VERSION 5.7 ;
BUSBITCHARS "[]" ;
DIVIDERCHAR "/" ;
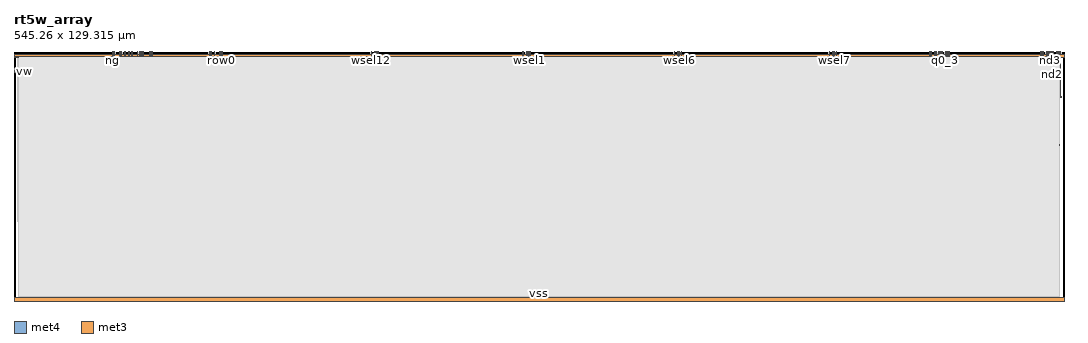
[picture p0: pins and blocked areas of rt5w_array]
MACRO rt5w_array
  CLASS BLOCK ;
  FOREIGN rt5w_array ;
  ORIGIN 0.000 117.195 ;
  SIZE 545.260 BY 129.315 ;
  SYMMETRY X Y ;
  PIN nd0
    DIRECTION INOUT ;
    USE SIGNAL ;
    PORT
      LAYER met4 ;
        RECT 485.380 11.970 485.680 12.120 ;
        RECT 485.365 11.470 485.695 11.970 ;
        RECT 485.380 9.620 485.680 11.470 ;
    END
  END nd0
  PIN nd1
    DIRECTION INOUT ;
    USE SIGNAL ;
    PORT
      LAYER met4 ;
        RECT 479.860 11.970 480.160 12.120 ;
        RECT 479.845 11.470 480.175 11.970 ;
        RECT 479.860 9.620 480.160 11.470 ;
    END
  END nd1
  PIN nd2
    DIRECTION INOUT ;
    USE SIGNAL ;
    PORT
      LAYER met4 ;
        RECT 543.340 11.970 543.640 12.120 ;
        RECT 543.325 11.470 543.655 11.970 ;
        RECT 543.340 -10.905 543.640 11.470 ;
        RECT 543.240 -11.405 543.740 -10.905 ;
    END
  END nd2
  PIN nd3
    DIRECTION INOUT ;
    USE SIGNAL ;
    PORT
      LAYER met4 ;
        RECT 537.820 11.970 538.120 12.120 ;
        RECT 537.805 11.470 538.135 11.970 ;
        RECT 537.820 9.620 538.120 11.470 ;
    END
  END nd3
  PIN ng
    DIRECTION INOUT ;
    USE SIGNAL ;
    PORT
      LAYER met4 ;
        RECT 51.140 11.970 51.440 12.120 ;
        RECT 51.125 11.470 51.455 11.970 ;
        RECT 51.140 9.620 51.440 11.470 ;
    END
  END ng
  PIN pg
    DIRECTION INOUT ;
    USE SIGNAL ;
    PORT
      LAYER met4 ;
        RECT 54.820 11.970 55.120 12.120 ;
        RECT 54.805 11.470 55.135 11.970 ;
        RECT 54.820 9.620 55.120 11.470 ;
    END
  END pg
  PIN pump_dn1
    DIRECTION INOUT ;
    USE SIGNAL ;
    PORT
      LAYER met4 ;
        RECT 66.780 11.970 67.080 12.120 ;
        RECT 66.765 11.470 67.095 11.970 ;
        RECT 66.780 9.620 67.080 11.470 ;
    END
  END pump_dn1
  PIN pump_dn2
    DIRECTION INOUT ;
    USE SIGNAL ;
    PORT
      LAYER met4 ;
        RECT 65.860 11.970 66.160 12.120 ;
        RECT 65.845 11.470 66.175 11.970 ;
        RECT 65.860 9.620 66.160 11.470 ;
    END
  END pump_dn2
  PIN pump_dn3
    DIRECTION INOUT ;
    USE SIGNAL ;
    PORT
      LAYER met4 ;
        RECT 71.380 11.970 71.680 12.120 ;
        RECT 71.365 11.470 71.695 11.970 ;
        RECT 71.380 9.620 71.680 11.470 ;
    END
  END pump_dn3
  PIN pump_up1
    DIRECTION INOUT ;
    USE SIGNAL ;
    PORT
      LAYER met4 ;
        RECT 64.940 11.970 65.240 12.120 ;
        RECT 64.925 11.470 65.255 11.970 ;
        RECT 64.940 9.620 65.240 11.470 ;
    END
  END pump_up1
  PIN pump_up2
    DIRECTION INOUT ;
    USE SIGNAL ;
    PORT
      LAYER met4 ;
        RECT 64.020 11.970 64.320 12.120 ;
        RECT 64.005 11.470 64.335 11.970 ;
        RECT 64.020 9.620 64.320 11.470 ;
    END
  END pump_up2
  PIN pump_up3
    DIRECTION INOUT ;
    USE SIGNAL ;
    PORT
      LAYER met4 ;
        RECT 70.460 11.970 70.760 12.120 ;
        RECT 70.445 11.470 70.775 11.970 ;
        RECT 70.460 9.620 70.760 11.470 ;
    END
  END pump_up3
  PIN q0_0
    DIRECTION INOUT ;
    USE SIGNAL ;
    PORT
      LAYER met4 ;
        RECT 484.460 11.970 484.760 12.120 ;
        RECT 484.445 11.470 484.775 11.970 ;
        RECT 484.460 9.620 484.760 11.470 ;
    END
  END q0_0
  PIN q0_1
    DIRECTION INOUT ;
    USE SIGNAL ;
    PORT
      LAYER met4 ;
        RECT 480.780 11.970 481.080 12.120 ;
        RECT 480.765 11.470 481.095 11.970 ;
        RECT 480.780 9.620 481.080 11.470 ;
    END
  END q0_1
  PIN q0_2
    DIRECTION INOUT ;
    USE SIGNAL ;
    PORT
      LAYER met4 ;
        RECT 481.700 11.970 482.000 12.120 ;
        RECT 481.685 11.470 482.015 11.970 ;
        RECT 481.700 9.620 482.000 11.470 ;
    END
  END q0_2
  PIN q0_3
    DIRECTION INOUT ;
    USE SIGNAL ;
    PORT
      LAYER met4 ;
        RECT 483.540 11.970 483.840 12.120 ;
        RECT 483.525 11.470 483.855 11.970 ;
        RECT 483.540 9.620 483.840 11.470 ;
    END
  END q0_3
  PIN q1_0
    DIRECTION INOUT ;
    USE SIGNAL ;
    PORT
      LAYER met4 ;
        RECT 478.940 11.970 479.240 12.120 ;
        RECT 478.925 11.470 479.255 11.970 ;
        RECT 478.940 9.620 479.240 11.470 ;
    END
  END q1_0
  PIN q1_1
    DIRECTION INOUT ;
    USE SIGNAL ;
    PORT
      LAYER met4 ;
        RECT 475.260 11.970 475.560 12.120 ;
        RECT 475.245 11.470 475.575 11.970 ;
        RECT 475.260 9.620 475.560 11.470 ;
    END
  END q1_1
  PIN q1_2
    DIRECTION INOUT ;
    USE SIGNAL ;
    PORT
      LAYER met4 ;
        RECT 476.180 11.970 476.480 12.120 ;
        RECT 476.165 11.470 476.495 11.970 ;
        RECT 476.180 9.620 476.480 11.470 ;
    END
  END q1_2
  PIN q1_3
    DIRECTION INOUT ;
    USE SIGNAL ;
    PORT
      LAYER met4 ;
        RECT 478.020 11.970 478.320 12.120 ;
        RECT 478.005 11.470 478.335 11.970 ;
        RECT 478.020 9.620 478.320 11.470 ;
    END
  END q1_3
  PIN q2_0
    DIRECTION INOUT ;
    USE SIGNAL ;
    PORT
      LAYER met4 ;
        RECT 542.760 -36.555 542.820 -36.055 ;
        RECT 542.420 11.970 542.720 12.120 ;
        RECT 542.405 11.470 542.735 11.970 ;
        RECT 542.420 9.620 542.720 11.470 ;
    END
  END q2_0
  PIN q2_1
    DIRECTION INOUT ;
    USE SIGNAL ;
    PORT
      LAYER met4 ;
        RECT 538.740 11.970 539.040 12.120 ;
        RECT 538.725 11.470 539.055 11.970 ;
        RECT 538.740 9.620 539.040 11.470 ;
    END
  END q2_1
  PIN q2_2
    DIRECTION INOUT ;
    USE SIGNAL ;
    PORT
      LAYER met4 ;
        RECT 539.660 11.970 539.960 12.120 ;
        RECT 539.645 11.470 539.975 11.970 ;
        RECT 539.660 9.620 539.960 11.470 ;
    END
  END q2_2
  PIN q2_3
    DIRECTION INOUT ;
    USE SIGNAL ;
    PORT
      LAYER met4 ;
        RECT 541.500 11.970 541.800 12.120 ;
        RECT 541.485 11.470 541.815 11.970 ;
        RECT 541.500 9.620 541.800 11.470 ;
    END
  END q2_3
  PIN q3_0
    DIRECTION INOUT ;
    USE SIGNAL ;
    PORT
      LAYER met4 ;
        RECT 536.900 11.970 537.200 12.120 ;
        RECT 536.885 11.470 537.215 11.970 ;
        RECT 536.900 9.620 537.200 11.470 ;
    END
  END q3_0
  PIN q3_1
    DIRECTION INOUT ;
    USE SIGNAL ;
    PORT
      LAYER met4 ;
        RECT 533.220 11.970 533.520 12.120 ;
        RECT 533.205 11.470 533.535 11.970 ;
        RECT 533.220 9.620 533.520 11.470 ;
    END
  END q3_1
  PIN q3_2
    DIRECTION INOUT ;
    USE SIGNAL ;
    PORT
      LAYER met4 ;
        RECT 534.140 11.970 534.440 12.120 ;
        RECT 534.125 11.470 534.455 11.970 ;
        RECT 534.140 9.620 534.440 11.470 ;
    END
  END q3_2
  PIN q3_3
    DIRECTION INOUT ;
    USE SIGNAL ;
    PORT
      LAYER met4 ;
        RECT 535.980 11.970 536.280 12.120 ;
        RECT 535.965 11.470 536.295 11.970 ;
        RECT 535.980 9.620 536.280 11.470 ;
    END
  END q3_3
  PIN row0
    DIRECTION INOUT ;
    USE SIGNAL ;
    PORT
      LAYER met4 ;
        RECT 107.720 11.970 108.020 12.120 ;
        RECT 107.705 11.470 108.035 11.970 ;
        RECT 107.720 9.620 108.020 11.470 ;
    END
  END row0
  PIN row1
    DIRECTION INOUT ;
    USE SIGNAL ;
    PORT
      LAYER met4 ;
        RECT 106.800 11.970 107.100 12.120 ;
        RECT 106.785 11.470 107.115 11.970 ;
        RECT 106.800 9.620 107.100 11.470 ;
    END
  END row1
  PIN row2
    DIRECTION INOUT ;
    USE SIGNAL ;
    PORT
      LAYER met4 ;
        RECT 104.040 11.970 104.340 12.120 ;
        RECT 104.025 11.470 104.355 11.970 ;
        RECT 104.040 9.620 104.340 11.470 ;
    END
  END row2
  PIN row3
    DIRECTION INOUT ;
    USE SIGNAL ;
    PORT
      LAYER met4 ;
        RECT 101.280 11.970 101.580 12.120 ;
        RECT 101.265 11.470 101.595 11.970 ;
        RECT 101.280 9.620 101.580 11.470 ;
    END
  END row3
  PIN vbn
    DIRECTION INOUT ;
    USE SIGNAL ;
    PORT
      LAYER met4 ;
        RECT 102.200 11.970 102.500 12.120 ;
        RECT 102.185 11.470 102.515 11.970 ;
        RECT 102.200 9.620 102.500 11.470 ;
    END
  END vbn
  PIN vdd
    DIRECTION INOUT ;
    USE SIGNAL ;
    PORT
      LAYER met3 ;
        RECT 0.000 9.120 2.500 9.620 ;
        RECT 0.000 9.620 542.760 10.920 ;
        RECT 542.760 9.120 545.260 10.920 ;
    END
  END vdd
  PIN vmid
    DIRECTION INOUT ;
    USE SIGNAL ;
    PORT
      LAYER met4 ;
        RECT 52.060 11.970 52.360 12.120 ;
        RECT 52.045 11.470 52.375 11.970 ;
        RECT 52.060 9.620 52.360 11.470 ;
    END
  END vmid
  PIN vss
    DIRECTION INOUT ;
    USE SIGNAL ;
    PORT
      LAYER met3 ;
        RECT 0.000 -117.195 545.260 -115.395 ;
    END
  END vss
  PIN vw
    DIRECTION INOUT ;
    USE SIGNAL ;
    PORT
      LAYER met3 ;
        RECT 0.000 1.690 2.500 1.990 ;
    END
  END vw
  PIN wsel0
    DIRECTION INOUT ;
    USE SIGNAL ;
    PORT
      LAYER met4 ;
        RECT 189.140 11.970 189.440 12.120 ;
        RECT 189.125 11.470 189.455 11.970 ;
        RECT 189.140 9.620 189.440 11.470 ;
    END
  END wsel0
  PIN wsel1
    DIRECTION INOUT ;
    USE SIGNAL ;
    PORT
      LAYER met4 ;
        RECT 267.800 11.970 268.100 12.120 ;
        RECT 267.785 11.470 268.115 11.970 ;
        RECT 267.800 9.620 268.100 11.470 ;
    END
  END wsel1
  PIN wsel10
    DIRECTION INOUT ;
    USE SIGNAL ;
    PORT
      LAYER met4 ;
        RECT 344.620 11.970 344.920 12.120 ;
        RECT 344.605 11.470 344.935 11.970 ;
        RECT 344.620 9.620 344.920 11.470 ;
    END
  END wsel10
  PIN wsel11
    DIRECTION INOUT ;
    USE SIGNAL ;
    PORT
      LAYER met4 ;
        RECT 425.120 11.970 425.420 12.120 ;
        RECT 425.105 11.470 425.435 11.970 ;
        RECT 425.120 9.620 425.420 11.470 ;
    END
  END wsel11
  PIN wsel12
    DIRECTION INOUT ;
    USE SIGNAL ;
    PORT
      LAYER met4 ;
        RECT 185.460 11.970 185.760 12.120 ;
        RECT 185.445 11.470 185.775 11.970 ;
        RECT 185.460 9.620 185.760 11.470 ;
    END
  END wsel12
  PIN wsel13
    DIRECTION INOUT ;
    USE SIGNAL ;
    PORT
      LAYER met4 ;
        RECT 264.120 11.970 264.420 12.120 ;
        RECT 264.105 11.470 264.435 11.970 ;
        RECT 264.120 9.620 264.420 11.470 ;
    END
  END wsel13
  PIN wsel14
    DIRECTION INOUT ;
    USE SIGNAL ;
    PORT
      LAYER met4 ;
        RECT 342.780 11.970 343.080 12.120 ;
        RECT 342.765 11.470 343.095 11.970 ;
        RECT 342.780 9.620 343.080 11.470 ;
    END
  END wsel14
  PIN wsel15
    DIRECTION INOUT ;
    USE SIGNAL ;
    PORT
      LAYER met4 ;
        RECT 423.280 11.970 423.580 12.120 ;
        RECT 423.265 11.470 423.595 11.970 ;
        RECT 423.280 9.620 423.580 11.470 ;
    END
  END wsel15
  PIN wsel16
    DIRECTION INOUT ;
    USE SIGNAL ;
    PORT
      LAYER met4 ;
        RECT 61.260 11.970 61.560 12.120 ;
        RECT 61.245 11.470 61.575 11.970 ;
        RECT 61.260 9.620 61.560 11.470 ;
    END
  END wsel16
  PIN wsel17
    DIRECTION INOUT ;
    USE SIGNAL ;
    PORT
      LAYER met4 ;
        RECT 59.420 11.970 59.720 12.120 ;
        RECT 59.405 11.470 59.735 11.970 ;
        RECT 59.420 9.620 59.720 11.470 ;
    END
  END wsel17
  PIN wsel18
    DIRECTION INOUT ;
    USE SIGNAL ;
    PORT
      LAYER met4 ;
        RECT 57.580 11.970 57.880 12.120 ;
        RECT 57.565 11.470 57.895 11.970 ;
        RECT 57.580 9.620 57.880 11.470 ;
    END
  END wsel18
  PIN wsel19
    DIRECTION INOUT ;
    USE SIGNAL ;
    PORT
      LAYER met4 ;
        RECT 55.740 11.970 56.040 12.120 ;
        RECT 55.725 11.470 56.055 11.970 ;
        RECT 55.740 9.620 56.040 11.470 ;
    END
  END wsel19
  PIN wsel2
    DIRECTION INOUT ;
    USE SIGNAL ;
    PORT
      LAYER met4 ;
        RECT 346.460 11.970 346.760 12.120 ;
        RECT 346.445 11.470 346.775 11.970 ;
        RECT 346.460 9.620 346.760 11.470 ;
    END
  END wsel2
  PIN wsel3
    DIRECTION INOUT ;
    USE SIGNAL ;
    PORT
      LAYER met4 ;
        RECT 426.960 11.970 427.260 12.120 ;
        RECT 426.945 11.470 427.275 11.970 ;
        RECT 426.960 9.620 427.260 11.470 ;
    END
  END wsel3
  PIN wsel4
    DIRECTION INOUT ;
    USE SIGNAL ;
    PORT
      LAYER met4 ;
        RECT 188.220 11.970 188.520 12.120 ;
        RECT 188.205 11.470 188.535 11.970 ;
        RECT 188.220 9.620 188.520 11.470 ;
    END
  END wsel4
  PIN wsel5
    DIRECTION INOUT ;
    USE SIGNAL ;
    PORT
      LAYER met4 ;
        RECT 266.880 11.970 267.180 12.120 ;
        RECT 266.865 11.470 267.195 11.970 ;
        RECT 266.880 9.620 267.180 11.470 ;
    END
  END wsel5
  PIN wsel6
    DIRECTION INOUT ;
    USE SIGNAL ;
    PORT
      LAYER met4 ;
        RECT 345.540 11.970 345.840 12.120 ;
        RECT 345.525 11.470 345.855 11.970 ;
        RECT 345.540 9.620 345.840 11.470 ;
    END
  END wsel6
  PIN wsel7
    DIRECTION INOUT ;
    USE SIGNAL ;
    PORT
      LAYER met4 ;
        RECT 426.040 11.970 426.340 12.120 ;
        RECT 426.025 11.470 426.355 11.970 ;
        RECT 426.040 9.620 426.340 11.470 ;
    END
  END wsel7
  PIN wsel8
    DIRECTION INOUT ;
    USE SIGNAL ;
    PORT
      LAYER met4 ;
        RECT 187.300 11.970 187.600 12.120 ;
        RECT 187.285 11.470 187.615 11.970 ;
        RECT 187.300 9.620 187.600 11.470 ;
    END
  END wsel8
  PIN wsel9
    DIRECTION INOUT ;
    USE SIGNAL ;
    PORT
      LAYER met4 ;
        RECT 265.960 11.970 266.260 12.120 ;
        RECT 265.945 11.470 266.275 11.970 ;
        RECT 265.960 9.620 266.260 11.470 ;
    END
  END wsel9
  OBS
    LAYER li1 ;
      RECT 2.500 -114.695 542.760 9.620 ;
    LAYER met1 ;
      RECT 2.500 -114.695 542.760 9.620 ;
    LAYER met2 ;
      RECT 2.500 -114.695 542.760 9.620 ;
    LAYER met3 ;
      RECT 1.725 -50.815 1.920 -50.485 ;
      RECT 1.920 -51.100 2.500 -50.200 ;
      RECT 1.725 -26.115 1.920 -25.785 ;
      RECT 1.920 -26.400 2.500 -25.500 ;
      RECT 2.500 -114.695 542.760 -11.305 ;
      RECT 542.760 -36.470 542.765 -36.140 ;
      RECT 1.725 -75.515 1.920 -75.185 ;
      RECT 1.920 -75.800 2.500 -74.900 ;
      RECT 2.500 -11.305 543.295 -11.005 ;
      RECT 543.295 -11.320 543.685 -10.990 ;
      RECT 2.500 -11.005 542.760 9.620 ;
      RECT 1.725 -1.415 1.920 -1.085 ;
      RECT 1.920 -1.700 2.500 -0.800 ;
      RECT 51.040 11.470 51.540 11.970 ;
      RECT 51.960 11.470 52.460 11.970 ;
      RECT 54.720 11.470 55.220 11.970 ;
      RECT 55.640 11.470 56.140 11.970 ;
      RECT 57.480 11.470 57.980 11.970 ;
      RECT 59.320 11.470 59.820 11.970 ;
      RECT 61.160 11.470 61.660 11.970 ;
      RECT 63.920 11.470 64.420 11.970 ;
      RECT 64.840 11.470 65.340 11.970 ;
      RECT 65.760 11.470 66.260 11.970 ;
      RECT 66.680 11.470 67.180 11.970 ;
      RECT 70.360 11.470 70.860 11.970 ;
      RECT 71.280 11.470 71.780 11.970 ;
      RECT 101.180 11.470 101.680 11.970 ;
      RECT 102.100 11.470 102.600 11.970 ;
      RECT 103.940 11.470 104.440 11.970 ;
      RECT 106.700 11.470 107.200 11.970 ;
      RECT 107.620 11.470 108.120 11.970 ;
      RECT 185.360 11.470 185.860 11.970 ;
      RECT 187.200 11.470 187.700 11.970 ;
      RECT 188.120 11.470 188.620 11.970 ;
      RECT 189.040 11.470 189.540 11.970 ;
      RECT 264.020 11.470 264.520 11.970 ;
      RECT 265.860 11.470 266.360 11.970 ;
      RECT 266.780 11.470 267.280 11.970 ;
      RECT 267.700 11.470 268.200 11.970 ;
      RECT 342.680 11.470 343.180 11.970 ;
      RECT 344.520 11.470 345.020 11.970 ;
      RECT 345.440 11.470 345.940 11.970 ;
      RECT 346.360 11.470 346.860 11.970 ;
      RECT 423.180 11.470 423.680 11.970 ;
      RECT 425.020 11.470 425.520 11.970 ;
      RECT 425.940 11.470 426.440 11.970 ;
      RECT 426.860 11.470 427.360 11.970 ;
      RECT 475.160 11.470 475.660 11.970 ;
      RECT 476.080 11.470 476.580 11.970 ;
      RECT 477.920 11.470 478.420 11.970 ;
      RECT 478.840 11.470 479.340 11.970 ;
      RECT 479.760 11.470 480.260 11.970 ;
      RECT 480.680 11.470 481.180 11.970 ;
      RECT 481.600 11.470 482.100 11.970 ;
      RECT 483.440 11.470 483.940 11.970 ;
      RECT 484.360 11.470 484.860 11.970 ;
      RECT 485.280 11.470 485.780 11.970 ;
      RECT 533.120 11.470 533.620 11.970 ;
      RECT 534.040 11.470 534.540 11.970 ;
      RECT 535.880 11.470 536.380 11.970 ;
      RECT 536.800 11.470 537.300 11.970 ;
      RECT 537.720 11.470 538.220 11.970 ;
      RECT 538.640 11.470 539.140 11.970 ;
      RECT 539.560 11.470 540.060 11.970 ;
      RECT 541.400 11.470 541.900 11.970 ;
      RECT 542.320 11.470 542.820 11.970 ;
      RECT 543.240 11.470 543.740 11.970 ;
    LAYER met4 ;
      RECT 1.620 -75.350 1.670 10.020 ;
      RECT 2.170 -75.350 2.220 10.020 ;
      RECT 1.670 -75.600 2.170 10.270 ;
      RECT 2.540 -116.295 3.140 -114.695 ;
      RECT 2.590 -116.545 3.090 -116.295 ;
      RECT 49.770 -116.295 50.370 -114.695 ;
      RECT 49.820 -116.545 50.320 -116.295 ;
      RECT 74.150 -116.295 74.750 -114.695 ;
      RECT 74.200 -116.545 74.700 -116.295 ;
      RECT 95.160 -116.295 95.760 -114.695 ;
      RECT 95.210 -116.545 95.710 -116.295 ;
      RECT 110.340 -116.295 110.940 -114.695 ;
      RECT 110.390 -116.545 110.890 -116.295 ;
      RECT 422.080 -116.295 422.680 -114.695 ;
      RECT 422.130 -116.545 422.630 -116.295 ;
      RECT 428.060 -116.295 428.660 -114.695 ;
      RECT 428.110 -116.545 428.610 -116.295 ;
      RECT 48.900 10.020 49.400 10.270 ;
      RECT 48.850 9.620 49.450 10.020 ;
      RECT 73.280 10.020 73.780 10.270 ;
      RECT 73.230 9.620 73.830 10.020 ;
      RECT 94.290 10.020 94.790 10.270 ;
      RECT 94.240 9.620 94.840 10.020 ;
      RECT 109.470 10.020 109.970 10.270 ;
      RECT 109.420 9.620 110.020 10.020 ;
      RECT 421.210 10.020 421.710 10.270 ;
      RECT 421.160 9.620 421.760 10.020 ;
      RECT 2.500 -114.695 542.760 9.620 ;
      RECT 532.000 -116.295 532.600 -114.695 ;
      RECT 532.050 -116.545 532.550 -116.295 ;
  END
END rt5w_array
END LIBRARY
